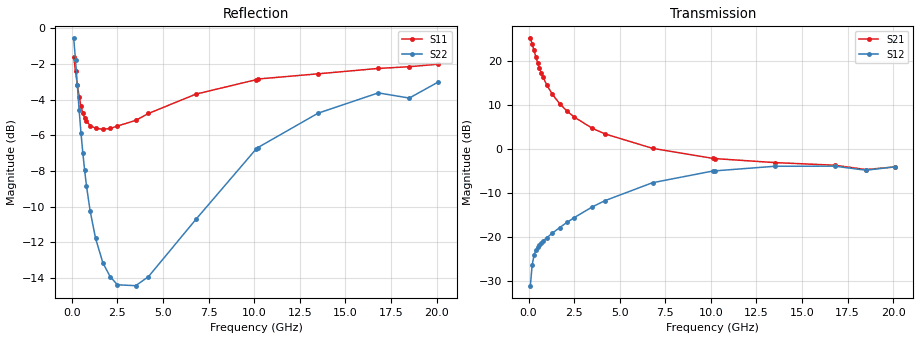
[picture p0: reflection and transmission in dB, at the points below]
!  Infineon Technologies AG
! BFR380L3 , PF131585-7, No.6, Th 09.10.01, soldered on pcb-board, measured with PP GSG850
!  Vce=3.0 V,  Ic=6.0 mA
! Common Emitter S-Parameters:  15. November 2001
#  GHz  S  MA  R  50
! f  S11  S21  S12  S22
! GHz  Mag  Ang  Mag  Ang  Mag  Ang  Mag  Ang
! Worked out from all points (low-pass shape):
!   201 points, 100 MHz to 20.1 GHz, reference 50 ohm
!   highest |S21| = 25.19 dB at 100 MHz (marker M1); lowest = -4.7 dB at 18.5 GHz (marker M2)
!   |S21| within 3 dB of the highest: start of sweep to 317.2 MHz
!   lowest |S11| = -5.7 dB at 1.7 GHz (marker M3), VSWR 3.17, Z = 15.8 - j1.11 ohm
!   |S11| at or under -10 dB: nowhere
!   |S22| runs from -14.6 to -0.6 dB; largest |S21 - S12| = 18
!   S11 on the Smith chart (normalised r, x): 100 MHz: 1.14, -3.21; 400 MHz: 0.37, -0.80; 1 GHz: 0.32, -0.24; 4.2 GHz: 0.31, +0.37; 10.2 GHz: 0.40, +1.18; 20.1 GHz: 0.97, +2.57
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0.1  0.8327 -31.2  18.17 159.2  0.02783 73.0  0.9372 -19.2
0.2  0.7591 -58.5  15.67 142.1  0.04794 61.9  0.8167 -34.7
0.3  0.6945 -80.5  13.24 129.4  0.06151 53.8  0.6925 -46.0
0.4  0.6435 -97.7  11.19 119.9  0.0702 48.9  0.5891 -54.0
0.5  0.6051 -111.3  9.572 112.6  0.07636 46.1  0.5094 -59.8
0.6  0.5783 -122.2  8.317 106.9  0.08175 44.7  0.4481 -64.2
0.7  0.5607 -131.1  7.329 102.1  0.08607 44.0  0.3999 -67.7
0.8  0.5483 -138.5  6.532 98.0  0.0903 43.9  0.3623 -70.5
1  0.5339 -150.6  5.361 91.4  0.09787 44.6  0.308 -75.0
1.3  0.5249 -163.9  4.219 83.5  0.1099 46.4  0.2576 -80.5
1.7  0.5209 -177.2  3.292 74.8  0.1273 48.7  0.2201 -87.1
2.1  0.524 172.5  2.712 67.4  0.1458 50.4  0.2012 -93.6
2.5  0.5321 163.9  2.314 60.7  0.1654 51.4  0.1909 -100.4
3.5  0.5518 145.9  1.72 46.0  0.2196 51.3  0.1898 -118.4
4.2  0.5771 135.7  1.484 37.2  0.2588 49.7  0.2012 -133.2
6.8  0.6538 104.8  1.018 11.2  0.4137 36.1  0.2912 179.8
10.1  0.7176 78.0  0.7831 -8.4  0.5614 13.9  0.4585 136.4
10.2  0.7208 77.0  0.7787 -9.0  0.5637 13.2  0.4631 135.1
13.5  0.7455 59.7  0.7006 -22.6  0.6362 -8.4  0.5781 103.1
16.8  0.7718 47.3  0.6539 -33.5  0.6378 -25.2  0.659 79.4
18.5  0.7804 45.5  0.5838 -41.2  0.5735 -33.9  0.6374 73.3
20.1  0.7933 38.1  0.6263 -44.6  0.6274 -39.1  0.7074 62.2
